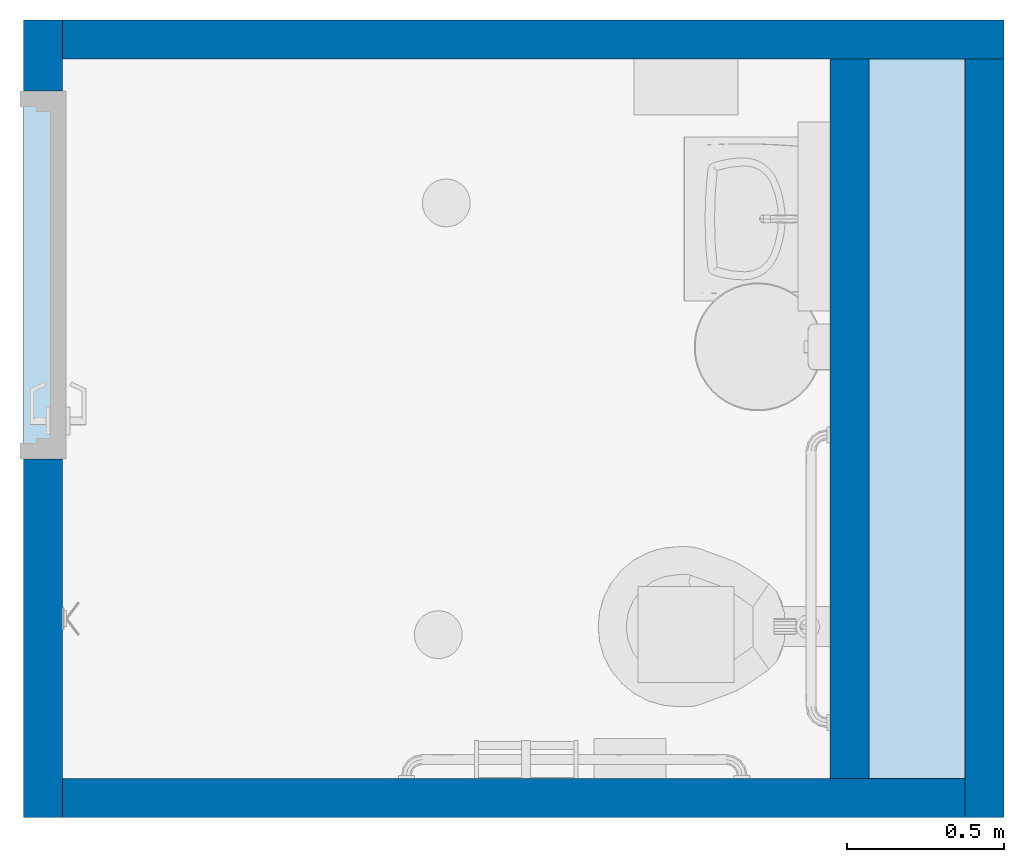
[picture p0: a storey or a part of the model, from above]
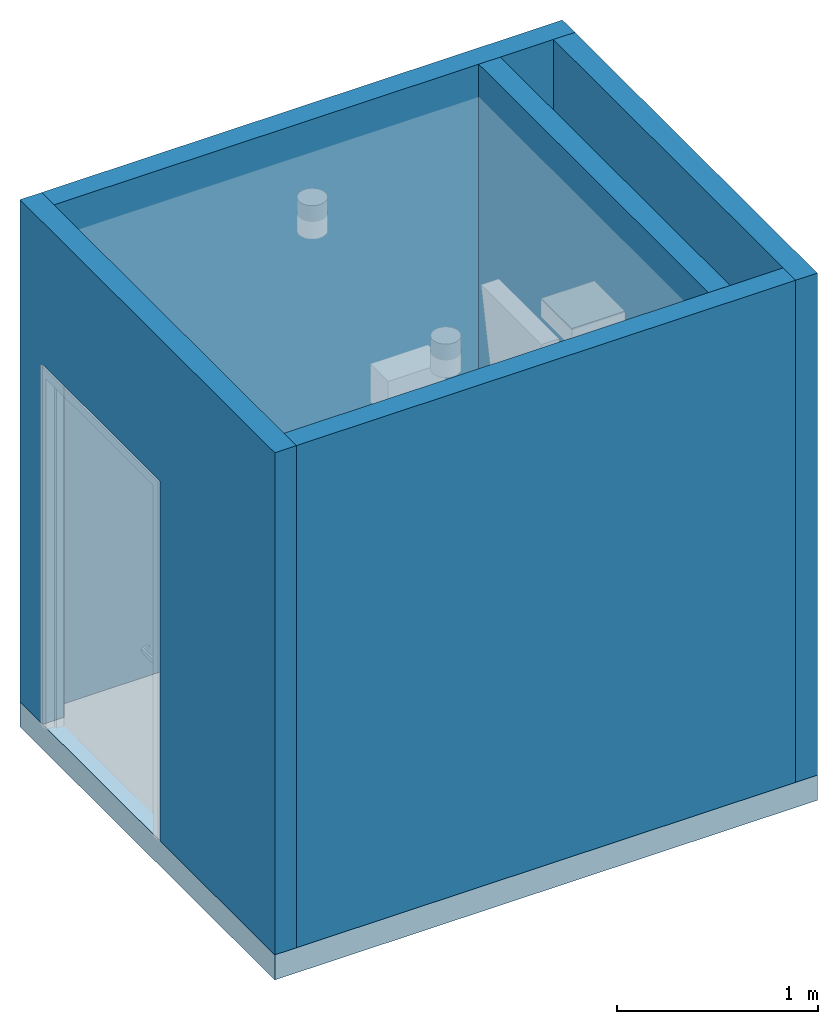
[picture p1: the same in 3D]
Properties of the parts of a building model (IFC2X3)

# File
Description: ViewDefinition [CoordinationView_V2.0]
File name: (ROOM CODE)
Time: 2018-06-28T13:28:19
Written by: The EXPRESS Data Manager Version 5.02.0100.07 : 28 Aug 2013
Made in: 20170223_1515(x64) - Exporter 18.0.0.420 - Alternate UI 18.0.0.420
Comment: STEP Physical File produced by: The EXPRESS Data Manager Version 5.02.0100.07 : 28 Aug 2013 * Module: EDMstepFileFactory/EDMstandAlone * Creation date: Thu Jun 28 13:28:19 2018 * Host: L106-OKC * Database: C:\Users\BHR~1.SPU\AppData\Local\Temp\{B5378B4D-486D-409C-A05C-CD3DFE366EDE}\ifc * Database version: 5507 * Database creation date: Thu Jun 28 13:28:17 2018 * Schema: IFC2X3 * Model: DataRepository.ifc * Model creation date: Thu Jun 28 13:28:18 2018 * Header model: DataRepository.ifc_HeaderModel * Header model creation date: Thu Jun 28 13:28:18 2018 * EDMuser: sdai-user * EDMgroup: sdai-group * License ID and type: 5605 : Permanent license. Expiry date: * EDMstepFileFactory options: 020000

# IfcProject, (ROOM CODE)
LongName: ROOM NAME (ROOM CODE); Phase: DRAFT

# IfcSite, Default
RefLatitude: 42, 21, 31, 181945; RefLongitude: -71, -3, -24, -263305; RefElevation: 0 ft

# IfcBuilding, OUTPATIENT / PACT CLINIC (Ch. 265)
LongName: OUTPATIENT / PACT CLINIC (Ch. 265)
Pset_BuildingCommon - NumberOfStoreys: 1

# IfcBuildingStorey, DATUM
In: OUTPATIENT / PACT CLINIC (Ch. 265)
LongName: DATUM; Elevation: 0 ft

# IfcSpace, TNPG1
In: DATUM
LongName: TOILET, GENERAL; InteriorOrExteriorSpace: INTERNAL
Pset_SpaceCommon - Reference: TOILET, GENERAL TNPG1; Category: Rooms

# IfcBuildingElementProxy: 12" x 12", Exhaust Register:12" x 12":1203693
In: TNPG1
Type - Classification: D3040100 Air Distribution Systems (Uniformat)
Pset_BuildingElementProxyCommon - Reference: 12" x 12"

# IfcBuildingElementProxy: A1067 - Mirror, Float Glass, ADA Accessible 12"x 6", A1067 - Mirror, Float Glass, ADA Accessible:A1067 - Mirror, Float Glass, ADA Accessible 12"x 6":804945
In: TNPG1
Type - Classification: CC (Uniformat)
Pset_BuildingElementProxyCommon - Reference: A1067 - Mirror, Float Glass, ADA Accessible 12"x 6"

# IfcBuildingElementProxy: A5075 - Dispenser, Soap, A5075 - Dispenser, Soap:A5075 - Dispenser, Soap:804944
In: TNPG1
Type - Classification: VV (Uniformat)
Pset_BuildingElementProxyCommon - Reference: A5075 - Dispenser, Soap

# IfcBuildingElementProxy: A5080 - Dispenser, Paper Towel, A5080 - Dispenser, Paper Towel:A5080 - Dispenser, Paper Towel:804943
In: TNPG1
Type - Classification: CC (Uniformat)
Pset_BuildingElementProxyCommon - Reference: A5080 - Dispenser, Paper Towel

# IfcBuildingElementProxy: A5090 - Dispenser, Sanitary Napkin, SS, Surface Mounted, A5090 - Dispenser, Sanitary Napkin, SS, Surface Mounted:A5090 - Dispenser, Sanitary Napkin, SS, Surface Mounted:804920
In: TNPG1
Type - Classification: CC (Uniformat)
Pset_BuildingElementProxyCommon - Reference: A5090 - Dispenser, Sanitary Napkin, SS, Surface Mounted

# IfcBuildingElementProxy: A5109 - Grab Bar, 1.25 in Dia, SS, 2 Wall, W-C Accessible_Improved (2)
In: TNPG1
Type - Classification: CC (Uniformat)
Pset_BuildingElementProxyCommon - Reference: A5109 - Grab Bar, 1.25 in Dia, SS, 2 Wall, W-C Accessible_Improved
Name (A5109 - Grab Bar, 1.25 in Dia, SS, 2 Wall, W-C Accessible_Improved:A5109 - Grab Bar, 1.25 in Dia, SS, 2 Wall, W-C Accessible_Improved:...)
804921
1514792

# IfcBuildingElementProxy: A5145 - Hook, Garment, Double, A5145 - Hook, Garment, Double:A5145 - Hook, Garment, Double:804922
In: TNPG1
Type - Classification: CC (Uniformat)
Pset_BuildingElementProxyCommon - Reference: A5145 - Hook, Garment, Double

# IfcBuildingElementProxy: A5200 - Dispenser, Toilet Tissue, SS, 2-Roll, Surface Mntd, A5200 - Dispenser, Toilet Tissue, SS, 2-Roll, Surface Mntd:A5200 - Dispenser, Toilet Tissue, SS, 2-Roll, Surface Mntd:804923
In: TNPG1
Type - Classification: CC (Uniformat)
Pset_BuildingElementProxyCommon - Reference: A5200 - Dispenser, Toilet Tissue, SS, 2-Roll, Surface Mntd

# IfcBuildingElementProxy: Duplex, Outlet, Duplex, Wall:Duplex:1514228
In: TNPG1
Pset_BuildingElementProxyCommon - Reference: Duplex

# IfcBuildingElementProxy: F2000 - Basket, Wastepaper, F2000 - Basket, Wastepaper:F2000 - Basket, Wastepaper:804924
In: TNPG1
Type - Classification: VV (Uniformat)
Pset_BuildingElementProxyCommon - Reference: F2000 - Basket, Wastepaper

# IfcBuildingElementProxy: P3100 - Lavatory, Viteous China, P3100 - Lavatory, Vitreous China:P3100 - Lavatory, Viteous China:804942
In: TNPG1
Type - Classification: CC (Uniformat)
Pset_BuildingElementProxyCommon - Reference: P3100 - Lavatory, Viteous China

# IfcBuildingElementProxy: P9050 - Toilet, Wall Hung, Siphon Jet, P9050 - Toilet, Wall Hung, Siphon Jet1:P9050 - Toilet, Wall Hung, Siphon Jet:804925
In: TNPG1
Type - Classification: CC (Uniformat)
Pset_BuildingElementProxyCommon - Reference: P9050 - Toilet, Wall Hung, Siphon Jet

# IfcCovering: Compound Ceiling:GWB on Mtl. Stud, Compound Ceiling:GWB on Mtl. Stud:804928
In: DATUM
PredefinedType: CEILING; Classification: C3030220 Suspended Ceilings - Gypsum Board (Uniformat); Material: <Unnamed> 0.302083 ft, gyp ceiling 0.0520833 ft
Pset_CoveringCommon - Reference: GWB on Mtl. Stud; Finish: gyp ceiling;; TotalThickness: 0.354167 ft

# IfcDoor: 42" x 84", Single - Flush:42" x 84":1508684
In: DATUM
Type - ParameterTakesPrecedence: no; Sizeable: no; Classification: C1020 Interior Doors (Uniformat)
OverallHeight: 7.16667 ft; OverallWidth: 3.83333 ft
Pset_DoorCommon - IsExternal: no; Reference: 42" x 84"

# IfcFlowTerminal: 6" (2)
In: TNPG1
Type - Classification: D5020220 Lighting - Incandescent (Uniformat)
Pset_DistributionFlowElementCommon - Reference: 6"
Name (Downlight - Recessed Can:6":...)
1204106
1204177

# IfcSlab: Floor:Generic - 6", Floor:Generic - 6":804915
In: DATUM
PredefinedType: FLOOR; Classification: B1010 Floor Construction (Uniformat); Material: <Unnamed> 0.5 ft
Pset_SlabCommon - LoadBearing: no; Reference: Generic - 6"; IsExternal: no; PitchAngle: 0 deg

# IfcWallStandardCase: Basic Wall:Interior - 4 7/8" (5)
In: DATUM
Type - PredefinedType: STANDARD; Material: <Unnamed> 0.40625 ft
Classification: B2010 Exterior Walls (Uniformat)
Pset_WallCommon - Reference: Interior - 4 7/8"; LoadBearing: no; ExtendToStructure: no; IsExternal: yes
Name (Basic Wall:Interior - 4 7/8":...)
804906
804907
804908
804909
804911
